VERSION 5.7 ;
  NOWIREEXTENSIONATPIN ON ;
  DIVIDERCHAR "/" ;
  BUSBITCHARS "[]" ;
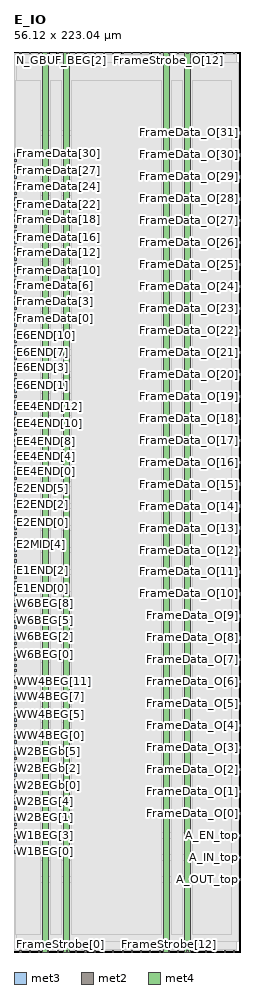
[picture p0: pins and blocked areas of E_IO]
MACRO E_IO
  CLASS BLOCK ;
  FOREIGN E_IO ;
  ORIGIN 0.000 0.000 ;
  SIZE 56.120 BY 223.040 ;
  PIN A_EN_top
    DIRECTION OUTPUT ;
    USE SIGNAL ;
    ANTENNADIFFAREA 0.702900 ;
    PORT
      LAYER met3 ;
        RECT 55.520 28.600 56.120 29.200 ;
    END
  END A_EN_top
  PIN A_IN_top
    DIRECTION OUTPUT ;
    USE SIGNAL ;
    ANTENNADIFFAREA 0.702900 ;
    PORT
      LAYER met3 ;
        RECT 55.520 23.160 56.120 23.760 ;
    END
  END A_IN_top
  PIN A_OUT_top
    DIRECTION INPUT ;
    USE SIGNAL ;
    ANTENNAGATEAREA 0.252000 ;
    PORT
      LAYER met3 ;
        RECT 55.520 17.720 56.120 18.320 ;
    END
  END A_OUT_top
  PIN E1END[0]
    DIRECTION INPUT ;
    USE SIGNAL ;
    ANTENNAGATEAREA 0.878700 ;
    ANTENNADIFFAREA 0.434700 ;
    PORT
      LAYER met3 ;
        RECT 0.000 89.800 0.600 90.400 ;
    END
  END E1END[0]
  PIN E1END[1]
    DIRECTION INPUT ;
    USE SIGNAL ;
    ANTENNAGATEAREA 0.444000 ;
    PORT
      LAYER met3 ;
        RECT 0.000 91.160 0.600 91.760 ;
    END
  END E1END[1]
  PIN E1END[2]
    DIRECTION INPUT ;
    USE SIGNAL ;
    ANTENNAGATEAREA 0.444000 ;
    PORT
      LAYER met3 ;
        RECT 0.000 92.520 0.600 93.120 ;
    END
  END E1END[2]
  PIN E1END[3]
    DIRECTION INPUT ;
    USE SIGNAL ;
    ANTENNAGATEAREA 0.444000 ;
    PORT
      LAYER met3 ;
        RECT 0.000 93.880 0.600 94.480 ;
    END
  END E1END[3]
  PIN E2END[0]
    DIRECTION INPUT ;
    USE SIGNAL ;
    ANTENNAGATEAREA 0.603000 ;
    PORT
      LAYER met3 ;
        RECT 0.000 106.120 0.600 106.720 ;
    END
  END E2END[0]
  PIN E2END[1]
    DIRECTION INPUT ;
    USE SIGNAL ;
    ANTENNAGATEAREA 0.972000 ;
    PORT
      LAYER met3 ;
        RECT 0.000 107.480 0.600 108.080 ;
    END
  END E2END[1]
  PIN E2END[2]
    DIRECTION INPUT ;
    USE SIGNAL ;
    ANTENNAGATEAREA 0.603000 ;
    PORT
      LAYER met3 ;
        RECT 0.000 108.840 0.600 109.440 ;
    END
  END E2END[2]
  PIN E2END[3]
    DIRECTION INPUT ;
    USE SIGNAL ;
    ANTENNAGATEAREA 0.972000 ;
    PORT
      LAYER met3 ;
        RECT 0.000 110.200 0.600 110.800 ;
    END
  END E2END[3]
  PIN E2END[4]
    DIRECTION INPUT ;
    USE SIGNAL ;
    ANTENNAGATEAREA 0.603000 ;
    PORT
      LAYER met3 ;
        RECT 0.000 111.560 0.600 112.160 ;
    END
  END E2END[4]
  PIN E2END[5]
    DIRECTION INPUT ;
    USE SIGNAL ;
    ANTENNAGATEAREA 0.477000 ;
    PORT
      LAYER met3 ;
        RECT 0.000 112.920 0.600 113.520 ;
    END
  END E2END[5]
  PIN E2END[6]
    DIRECTION INPUT ;
    USE SIGNAL ;
    ANTENNAGATEAREA 0.477000 ;
    PORT
      LAYER met3 ;
        RECT 0.000 114.280 0.600 114.880 ;
    END
  END E2END[6]
  PIN E2END[7]
    DIRECTION INPUT ;
    USE SIGNAL ;
    ANTENNAGATEAREA 0.477000 ;
    PORT
      LAYER met3 ;
        RECT 0.000 115.640 0.600 116.240 ;
    END
  END E2END[7]
  PIN E2MID[0]
    DIRECTION INPUT ;
    USE SIGNAL ;
    ANTENNAGATEAREA 0.636000 ;
    PORT
      LAYER met3 ;
        RECT 0.000 95.240 0.600 95.840 ;
    END
  END E2MID[0]
  PIN E2MID[1]
    DIRECTION INPUT ;
    USE SIGNAL ;
    ANTENNAGATEAREA 0.636000 ;
    PORT
      LAYER met3 ;
        RECT 0.000 96.600 0.600 97.200 ;
    END
  END E2MID[1]
  PIN E2MID[2]
    DIRECTION INPUT ;
    USE SIGNAL ;
    ANTENNAGATEAREA 0.636000 ;
    PORT
      LAYER met3 ;
        RECT 0.000 97.960 0.600 98.560 ;
    END
  END E2MID[2]
  PIN E2MID[3]
    DIRECTION INPUT ;
    USE SIGNAL ;
    ANTENNAGATEAREA 0.636000 ;
    PORT
      LAYER met3 ;
        RECT 0.000 99.320 0.600 99.920 ;
    END
  END E2MID[3]
  PIN E2MID[4]
    DIRECTION INPUT ;
    USE SIGNAL ;
    ANTENNAGATEAREA 0.636000 ;
    PORT
      LAYER met3 ;
        RECT 0.000 100.680 0.600 101.280 ;
    END
  END E2MID[4]
  PIN E2MID[5]
    DIRECTION INPUT ;
    USE SIGNAL ;
    ANTENNAGATEAREA 0.636000 ;
    PORT
      LAYER met3 ;
        RECT 0.000 102.040 0.600 102.640 ;
    END
  END E2MID[5]
  PIN E2MID[6]
    DIRECTION INPUT ;
    USE SIGNAL ;
    ANTENNAGATEAREA 0.636000 ;
    PORT
      LAYER met3 ;
        RECT 0.000 103.400 0.600 104.000 ;
    END
  END E2MID[6]
  PIN E2MID[7]
    DIRECTION INPUT ;
    USE SIGNAL ;
    ANTENNAGATEAREA 0.762000 ;
    PORT
      LAYER met3 ;
        RECT 0.000 104.760 0.600 105.360 ;
    END
  END E2MID[7]
  PIN E6END[0]
    DIRECTION INPUT ;
    USE SIGNAL ;
    ANTENNAGATEAREA 0.795000 ;
    PORT
      LAYER met3 ;
        RECT 0.000 138.760 0.600 139.360 ;
    END
  END E6END[0]
  PIN E6END[10]
    DIRECTION INPUT ;
    USE SIGNAL ;
    ANTENNAGATEAREA 0.636000 ;
    PORT
      LAYER met3 ;
        RECT 0.000 152.360 0.600 152.960 ;
    END
  END E6END[10]
  PIN E6END[11]
    DIRECTION INPUT ;
    USE SIGNAL ;
    ANTENNAGATEAREA 0.477000 ;
    PORT
      LAYER met3 ;
        RECT 0.000 153.720 0.600 154.320 ;
    END
  END E6END[11]
  PIN E6END[1]
    DIRECTION INPUT ;
    USE SIGNAL ;
    ANTENNAGATEAREA 0.954000 ;
    PORT
      LAYER met3 ;
        RECT 0.000 140.120 0.600 140.720 ;
    END
  END E6END[1]
  PIN E6END[2]
    DIRECTION INPUT ;
    USE SIGNAL ;
    ANTENNAGATEAREA 0.795000 ;
    PORT
      LAYER met3 ;
        RECT 0.000 141.480 0.600 142.080 ;
    END
  END E6END[2]
  PIN E6END[3]
    DIRECTION INPUT ;
    USE SIGNAL ;
    ANTENNAGATEAREA 0.954000 ;
    PORT
      LAYER met3 ;
        RECT 0.000 142.840 0.600 143.440 ;
    END
  END E6END[3]
  PIN E6END[4]
    DIRECTION INPUT ;
    USE SIGNAL ;
    ANTENNAGATEAREA 0.954000 ;
    PORT
      LAYER met3 ;
        RECT 0.000 144.200 0.600 144.800 ;
    END
  END E6END[4]
  PIN E6END[5]
    DIRECTION INPUT ;
    USE SIGNAL ;
    ANTENNAGATEAREA 0.954000 ;
    PORT
      LAYER met3 ;
        RECT 0.000 145.560 0.600 146.160 ;
    END
  END E6END[5]
  PIN E6END[6]
    DIRECTION INPUT ;
    USE SIGNAL ;
    ANTENNAGATEAREA 0.954000 ;
    PORT
      LAYER met3 ;
        RECT 0.000 146.920 0.600 147.520 ;
    END
  END E6END[6]
  PIN E6END[7]
    DIRECTION INPUT ;
    USE SIGNAL ;
    ANTENNAGATEAREA 0.954000 ;
    PORT
      LAYER met3 ;
        RECT 0.000 148.280 0.600 148.880 ;
    END
  END E6END[7]
  PIN E6END[8]
    DIRECTION INPUT ;
    USE SIGNAL ;
    ANTENNAGATEAREA 0.636000 ;
    PORT
      LAYER met3 ;
        RECT 0.000 149.640 0.600 150.240 ;
    END
  END E6END[8]
  PIN E6END[9]
    DIRECTION INPUT ;
    USE SIGNAL ;
    ANTENNAGATEAREA 0.477000 ;
    PORT
      LAYER met3 ;
        RECT 0.000 151.000 0.600 151.600 ;
    END
  END E6END[9]
  PIN EE4END[0]
    DIRECTION INPUT ;
    USE SIGNAL ;
    ANTENNAGATEAREA 0.477000 ;
    PORT
      LAYER met3 ;
        RECT 0.000 117.000 0.600 117.600 ;
    END
  END EE4END[0]
  PIN EE4END[10]
    DIRECTION INPUT ;
    USE SIGNAL ;
    ANTENNAGATEAREA 0.477000 ;
    PORT
      LAYER met3 ;
        RECT 0.000 130.600 0.600 131.200 ;
    END
  END EE4END[10]
  PIN EE4END[11]
    DIRECTION INPUT ;
    USE SIGNAL ;
    ANTENNAGATEAREA 0.477000 ;
    PORT
      LAYER met3 ;
        RECT 0.000 131.960 0.600 132.560 ;
    END
  END EE4END[11]
  PIN EE4END[12]
    DIRECTION INPUT ;
    USE SIGNAL ;
    ANTENNAGATEAREA 0.477000 ;
    PORT
      LAYER met3 ;
        RECT 0.000 133.320 0.600 133.920 ;
    END
  END EE4END[12]
  PIN EE4END[13]
    DIRECTION INPUT ;
    USE SIGNAL ;
    ANTENNAGATEAREA 0.477000 ;
    PORT
      LAYER met3 ;
        RECT 0.000 134.680 0.600 135.280 ;
    END
  END EE4END[13]
  PIN EE4END[14]
    DIRECTION INPUT ;
    USE SIGNAL ;
    ANTENNAGATEAREA 0.911700 ;
    ANTENNADIFFAREA 0.434700 ;
    PORT
      LAYER met3 ;
        RECT 0.000 136.040 0.600 136.640 ;
    END
  END EE4END[14]
  PIN EE4END[15]
    DIRECTION INPUT ;
    USE SIGNAL ;
    ANTENNAGATEAREA 0.477000 ;
    PORT
      LAYER met3 ;
        RECT 0.000 137.400 0.600 138.000 ;
    END
  END EE4END[15]
  PIN EE4END[1]
    DIRECTION INPUT ;
    USE SIGNAL ;
    ANTENNAGATEAREA 0.477000 ;
    PORT
      LAYER met3 ;
        RECT 0.000 118.360 0.600 118.960 ;
    END
  END EE4END[1]
  PIN EE4END[2]
    DIRECTION INPUT ;
    USE SIGNAL ;
    ANTENNAGATEAREA 0.477000 ;
    PORT
      LAYER met3 ;
        RECT 0.000 119.720 0.600 120.320 ;
    END
  END EE4END[2]
  PIN EE4END[3]
    DIRECTION INPUT ;
    USE SIGNAL ;
    ANTENNAGATEAREA 0.477000 ;
    PORT
      LAYER met3 ;
        RECT 0.000 121.080 0.600 121.680 ;
    END
  END EE4END[3]
  PIN EE4END[4]
    DIRECTION INPUT ;
    USE SIGNAL ;
    ANTENNAGATEAREA 0.477000 ;
    PORT
      LAYER met3 ;
        RECT 0.000 122.440 0.600 123.040 ;
    END
  END EE4END[4]
  PIN EE4END[5]
    DIRECTION INPUT ;
    USE SIGNAL ;
    ANTENNAGATEAREA 0.477000 ;
    PORT
      LAYER met3 ;
        RECT 0.000 123.800 0.600 124.400 ;
    END
  END EE4END[5]
  PIN EE4END[6]
    DIRECTION INPUT ;
    USE SIGNAL ;
    ANTENNAGATEAREA 0.477000 ;
    PORT
      LAYER met3 ;
        RECT 0.000 125.160 0.600 125.760 ;
    END
  END EE4END[6]
  PIN EE4END[7]
    DIRECTION INPUT ;
    USE SIGNAL ;
    ANTENNAGATEAREA 0.477000 ;
    PORT
      LAYER met3 ;
        RECT 0.000 126.520 0.600 127.120 ;
    END
  END EE4END[7]
  PIN EE4END[8]
    DIRECTION INPUT ;
    USE SIGNAL ;
    ANTENNAGATEAREA 0.477000 ;
    PORT
      LAYER met3 ;
        RECT 0.000 127.880 0.600 128.480 ;
    END
  END EE4END[8]
  PIN EE4END[9]
    DIRECTION INPUT ;
    USE SIGNAL ;
    ANTENNAGATEAREA 0.477000 ;
    PORT
      LAYER met3 ;
        RECT 0.000 129.240 0.600 129.840 ;
    END
  END EE4END[9]
  PIN FrameData[0]
    DIRECTION INPUT ;
    USE SIGNAL ;
    ANTENNAGATEAREA 1.070700 ;
    ANTENNADIFFAREA 0.434700 ;
    PORT
      LAYER met3 ;
        RECT 0.000 155.080 0.600 155.680 ;
    END
  END FrameData[0]
  PIN FrameData[10]
    DIRECTION INPUT ;
    USE SIGNAL ;
    ANTENNAGATEAREA 0.795000 ;
    PORT
      LAYER met3 ;
        RECT 0.000 168.680 0.600 169.280 ;
    END
  END FrameData[10]
  PIN FrameData[11]
    DIRECTION INPUT ;
    USE SIGNAL ;
    ANTENNAGATEAREA 1.229700 ;
    ANTENNADIFFAREA 0.434700 ;
    PORT
      LAYER met3 ;
        RECT 0.000 170.040 0.600 170.640 ;
    END
  END FrameData[11]
  PIN FrameData[12]
    DIRECTION INPUT ;
    USE SIGNAL ;
    ANTENNAGATEAREA 1.229700 ;
    ANTENNADIFFAREA 0.434700 ;
    PORT
      LAYER met3 ;
        RECT 0.000 171.400 0.600 172.000 ;
    END
  END FrameData[12]
  PIN FrameData[13]
    DIRECTION INPUT ;
    USE SIGNAL ;
    ANTENNAGATEAREA 0.795000 ;
    PORT
      LAYER met3 ;
        RECT 0.000 172.760 0.600 173.360 ;
    END
  END FrameData[13]
  PIN FrameData[14]
    DIRECTION INPUT ;
    USE SIGNAL ;
    ANTENNAGATEAREA 0.795000 ;
    PORT
      LAYER met3 ;
        RECT 0.000 174.120 0.600 174.720 ;
    END
  END FrameData[14]
  PIN FrameData[15]
    DIRECTION INPUT ;
    USE SIGNAL ;
    ANTENNAGATEAREA 0.795000 ;
    PORT
      LAYER met3 ;
        RECT 0.000 175.480 0.600 176.080 ;
    END
  END FrameData[15]
  PIN FrameData[16]
    DIRECTION INPUT ;
    USE SIGNAL ;
    ANTENNAGATEAREA 0.795000 ;
    PORT
      LAYER met3 ;
        RECT 0.000 176.840 0.600 177.440 ;
    END
  END FrameData[16]
  PIN FrameData[17]
    DIRECTION INPUT ;
    USE SIGNAL ;
    ANTENNAGATEAREA 0.795000 ;
    PORT
      LAYER met3 ;
        RECT 0.000 178.200 0.600 178.800 ;
    END
  END FrameData[17]
  PIN FrameData[18]
    DIRECTION INPUT ;
    USE SIGNAL ;
    ANTENNAGATEAREA 0.795000 ;
    PORT
      LAYER met3 ;
        RECT 0.000 179.560 0.600 180.160 ;
    END
  END FrameData[18]
  PIN FrameData[19]
    DIRECTION INPUT ;
    USE SIGNAL ;
    ANTENNAGATEAREA 0.795000 ;
    PORT
      LAYER met3 ;
        RECT 0.000 180.920 0.600 181.520 ;
    END
  END FrameData[19]
  PIN FrameData[1]
    DIRECTION INPUT ;
    USE SIGNAL ;
    ANTENNAGATEAREA 0.636000 ;
    PORT
      LAYER met3 ;
        RECT 0.000 156.440 0.600 157.040 ;
    END
  END FrameData[1]
  PIN FrameData[20]
    DIRECTION INPUT ;
    USE SIGNAL ;
    ANTENNAGATEAREA 1.229700 ;
    ANTENNADIFFAREA 0.434700 ;
    PORT
      LAYER met3 ;
        RECT 0.000 182.280 0.600 182.880 ;
    END
  END FrameData[20]
  PIN FrameData[21]
    DIRECTION INPUT ;
    USE SIGNAL ;
    ANTENNAGATEAREA 0.795000 ;
    PORT
      LAYER met3 ;
        RECT 0.000 183.640 0.600 184.240 ;
    END
  END FrameData[21]
  PIN FrameData[22]
    DIRECTION INPUT ;
    USE SIGNAL ;
    ANTENNAGATEAREA 0.795000 ;
    PORT
      LAYER met3 ;
        RECT 0.000 185.000 0.600 185.600 ;
    END
  END FrameData[22]
  PIN FrameData[23]
    DIRECTION INPUT ;
    USE SIGNAL ;
    ANTENNAGATEAREA 0.795000 ;
    PORT
      LAYER met3 ;
        RECT 0.000 186.360 0.600 186.960 ;
    END
  END FrameData[23]
  PIN FrameData[24]
    DIRECTION INPUT ;
    USE SIGNAL ;
    ANTENNAGATEAREA 0.795000 ;
    PORT
      LAYER met3 ;
        RECT 0.000 187.720 0.600 188.320 ;
    END
  END FrameData[24]
  PIN FrameData[25]
    DIRECTION INPUT ;
    USE SIGNAL ;
    ANTENNAGATEAREA 0.795000 ;
    PORT
      LAYER met3 ;
        RECT 0.000 189.080 0.600 189.680 ;
    END
  END FrameData[25]
  PIN FrameData[26]
    DIRECTION INPUT ;
    USE SIGNAL ;
    ANTENNAGATEAREA 0.795000 ;
    PORT
      LAYER met3 ;
        RECT 0.000 190.440 0.600 191.040 ;
    END
  END FrameData[26]
  PIN FrameData[27]
    DIRECTION INPUT ;
    USE SIGNAL ;
    ANTENNAGATEAREA 0.795000 ;
    PORT
      LAYER met3 ;
        RECT 0.000 191.800 0.600 192.400 ;
    END
  END FrameData[27]
  PIN FrameData[28]
    DIRECTION INPUT ;
    USE SIGNAL ;
    ANTENNAGATEAREA 0.795000 ;
    PORT
      LAYER met3 ;
        RECT 0.000 193.160 0.600 193.760 ;
    END
  END FrameData[28]
  PIN FrameData[29]
    DIRECTION INPUT ;
    USE SIGNAL ;
    ANTENNAGATEAREA 0.795000 ;
    PORT
      LAYER met3 ;
        RECT 0.000 194.520 0.600 195.120 ;
    END
  END FrameData[29]
  PIN FrameData[2]
    DIRECTION INPUT ;
    USE SIGNAL ;
    ANTENNAGATEAREA 0.636000 ;
    PORT
      LAYER met3 ;
        RECT 0.000 157.800 0.600 158.400 ;
    END
  END FrameData[2]
  PIN FrameData[30]
    DIRECTION INPUT ;
    USE SIGNAL ;
    ANTENNAGATEAREA 1.229700 ;
    ANTENNADIFFAREA 0.434700 ;
    PORT
      LAYER met3 ;
        RECT 0.000 195.880 0.600 196.480 ;
    END
  END FrameData[30]
  PIN FrameData[31]
    DIRECTION INPUT ;
    USE SIGNAL ;
    ANTENNAGATEAREA 0.795000 ;
    PORT
      LAYER met3 ;
        RECT 0.000 197.240 0.600 197.840 ;
    END
  END FrameData[31]
  PIN FrameData[3]
    DIRECTION INPUT ;
    USE SIGNAL ;
    ANTENNAGATEAREA 0.636000 ;
    PORT
      LAYER met3 ;
        RECT 0.000 159.160 0.600 159.760 ;
    END
  END FrameData[3]
  PIN FrameData[4]
    DIRECTION INPUT ;
    USE SIGNAL ;
    ANTENNAGATEAREA 0.636000 ;
    PORT
      LAYER met3 ;
        RECT 0.000 160.520 0.600 161.120 ;
    END
  END FrameData[4]
  PIN FrameData[5]
    DIRECTION INPUT ;
    USE SIGNAL ;
    ANTENNAGATEAREA 0.636000 ;
    PORT
      LAYER met3 ;
        RECT 0.000 161.880 0.600 162.480 ;
    END
  END FrameData[5]
  PIN FrameData[6]
    DIRECTION INPUT ;
    USE SIGNAL ;
    ANTENNAGATEAREA 0.636000 ;
    PORT
      LAYER met3 ;
        RECT 0.000 163.240 0.600 163.840 ;
    END
  END FrameData[6]
  PIN FrameData[7]
    DIRECTION INPUT ;
    USE SIGNAL ;
    ANTENNAGATEAREA 0.636000 ;
    PORT
      LAYER met3 ;
        RECT 0.000 164.600 0.600 165.200 ;
    END
  END FrameData[7]
  PIN FrameData[8]
    DIRECTION INPUT ;
    USE SIGNAL ;
    ANTENNAGATEAREA 0.795000 ;
    PORT
      LAYER met3 ;
        RECT 0.000 165.960 0.600 166.560 ;
    END
  END FrameData[8]
  PIN FrameData[9]
    DIRECTION INPUT ;
    USE SIGNAL ;
    ANTENNAGATEAREA 0.795000 ;
    PORT
      LAYER met3 ;
        RECT 0.000 167.320 0.600 167.920 ;
    END
  END FrameData[9]
  PIN FrameData_O[0]
    DIRECTION OUTPUT ;
    USE SIGNAL ;
    ANTENNADIFFAREA 0.702900 ;
    PORT
      LAYER met3 ;
        RECT 55.520 34.040 56.120 34.640 ;
    END
  END FrameData_O[0]
  PIN FrameData_O[10]
    DIRECTION OUTPUT ;
    USE SIGNAL ;
    ANTENNADIFFAREA 0.702900 ;
    PORT
      LAYER met3 ;
        RECT 55.520 88.440 56.120 89.040 ;
    END
  END FrameData_O[10]
  PIN FrameData_O[11]
    DIRECTION OUTPUT ;
    USE SIGNAL ;
    ANTENNADIFFAREA 0.702900 ;
    PORT
      LAYER met3 ;
        RECT 55.520 93.880 56.120 94.480 ;
    END
  END FrameData_O[11]
  PIN FrameData_O[12]
    DIRECTION OUTPUT ;
    USE SIGNAL ;
    ANTENNADIFFAREA 0.702900 ;
    PORT
      LAYER met3 ;
        RECT 55.520 99.320 56.120 99.920 ;
    END
  END FrameData_O[12]
  PIN FrameData_O[13]
    DIRECTION OUTPUT ;
    USE SIGNAL ;
    ANTENNADIFFAREA 0.702900 ;
    PORT
      LAYER met3 ;
        RECT 55.520 104.760 56.120 105.360 ;
    END
  END FrameData_O[13]
  PIN FrameData_O[14]
    DIRECTION OUTPUT ;
    USE SIGNAL ;
    ANTENNADIFFAREA 0.702900 ;
    PORT
      LAYER met3 ;
        RECT 55.520 110.200 56.120 110.800 ;
    END
  END FrameData_O[14]
  PIN FrameData_O[15]
    DIRECTION OUTPUT ;
    USE SIGNAL ;
    ANTENNADIFFAREA 0.702900 ;
    PORT
      LAYER met3 ;
        RECT 55.520 115.640 56.120 116.240 ;
    END
  END FrameData_O[15]
  PIN FrameData_O[16]
    DIRECTION OUTPUT ;
    USE SIGNAL ;
    ANTENNADIFFAREA 0.702900 ;
    PORT
      LAYER met3 ;
        RECT 55.520 121.080 56.120 121.680 ;
    END
  END FrameData_O[16]
  PIN FrameData_O[17]
    DIRECTION OUTPUT ;
    USE SIGNAL ;
    ANTENNADIFFAREA 0.702900 ;
    PORT
      LAYER met3 ;
        RECT 55.520 126.520 56.120 127.120 ;
    END
  END FrameData_O[17]
  PIN FrameData_O[18]
    DIRECTION OUTPUT ;
    USE SIGNAL ;
    ANTENNADIFFAREA 0.702900 ;
    PORT
      LAYER met3 ;
        RECT 55.520 131.960 56.120 132.560 ;
    END
  END FrameData_O[18]
  PIN FrameData_O[19]
    DIRECTION OUTPUT ;
    USE SIGNAL ;
    ANTENNADIFFAREA 0.702900 ;
    PORT
      LAYER met3 ;
        RECT 55.520 137.400 56.120 138.000 ;
    END
  END FrameData_O[19]
  PIN FrameData_O[1]
    DIRECTION OUTPUT ;
    USE SIGNAL ;
    ANTENNADIFFAREA 0.702900 ;
    PORT
      LAYER met3 ;
        RECT 55.520 39.480 56.120 40.080 ;
    END
  END FrameData_O[1]
  PIN FrameData_O[20]
    DIRECTION OUTPUT ;
    USE SIGNAL ;
    ANTENNADIFFAREA 0.702900 ;
    PORT
      LAYER met3 ;
        RECT 55.520 142.840 56.120 143.440 ;
    END
  END FrameData_O[20]
  PIN FrameData_O[21]
    DIRECTION OUTPUT ;
    USE SIGNAL ;
    ANTENNADIFFAREA 0.702900 ;
    PORT
      LAYER met3 ;
        RECT 55.520 148.280 56.120 148.880 ;
    END
  END FrameData_O[21]
  PIN FrameData_O[22]
    DIRECTION OUTPUT ;
    USE SIGNAL ;
    ANTENNADIFFAREA 0.702900 ;
    PORT
      LAYER met3 ;
        RECT 55.520 153.720 56.120 154.320 ;
    END
  END FrameData_O[22]
  PIN FrameData_O[23]
    DIRECTION OUTPUT ;
    USE SIGNAL ;
    ANTENNADIFFAREA 0.702900 ;
    PORT
      LAYER met3 ;
        RECT 55.520 159.160 56.120 159.760 ;
    END
  END FrameData_O[23]
  PIN FrameData_O[24]
    DIRECTION OUTPUT ;
    USE SIGNAL ;
    ANTENNADIFFAREA 0.702900 ;
    PORT
      LAYER met3 ;
        RECT 55.520 164.600 56.120 165.200 ;
    END
  END FrameData_O[24]
  PIN FrameData_O[25]
    DIRECTION OUTPUT ;
    USE SIGNAL ;
    ANTENNADIFFAREA 0.702900 ;
    PORT
      LAYER met3 ;
        RECT 55.520 170.040 56.120 170.640 ;
    END
  END FrameData_O[25]
  PIN FrameData_O[26]
    DIRECTION OUTPUT ;
    USE SIGNAL ;
    ANTENNADIFFAREA 0.702900 ;
    PORT
      LAYER met3 ;
        RECT 55.520 175.480 56.120 176.080 ;
    END
  END FrameData_O[26]
  PIN FrameData_O[27]
    DIRECTION OUTPUT ;
    USE SIGNAL ;
    ANTENNADIFFAREA 0.702900 ;
    PORT
      LAYER met3 ;
        RECT 55.520 180.920 56.120 181.520 ;
    END
  END FrameData_O[27]
  PIN FrameData_O[28]
    DIRECTION OUTPUT ;
    USE SIGNAL ;
    ANTENNADIFFAREA 0.702900 ;
    PORT
      LAYER met3 ;
        RECT 55.520 186.360 56.120 186.960 ;
    END
  END FrameData_O[28]
  PIN FrameData_O[29]
    DIRECTION OUTPUT ;
    USE SIGNAL ;
    ANTENNADIFFAREA 0.702900 ;
    PORT
      LAYER met3 ;
        RECT 55.520 191.800 56.120 192.400 ;
    END
  END FrameData_O[29]
  PIN FrameData_O[2]
    DIRECTION OUTPUT ;
    USE SIGNAL ;
    ANTENNADIFFAREA 0.702900 ;
    PORT
      LAYER met3 ;
        RECT 55.520 44.920 56.120 45.520 ;
    END
  END FrameData_O[2]
  PIN FrameData_O[30]
    DIRECTION OUTPUT ;
    USE SIGNAL ;
    ANTENNADIFFAREA 0.702900 ;
    PORT
      LAYER met3 ;
        RECT 55.520 197.240 56.120 197.840 ;
    END
  END FrameData_O[30]
  PIN FrameData_O[31]
    DIRECTION OUTPUT ;
    USE SIGNAL ;
    ANTENNADIFFAREA 0.702900 ;
    PORT
      LAYER met3 ;
        RECT 55.520 202.680 56.120 203.280 ;
    END
  END FrameData_O[31]
  PIN FrameData_O[3]
    DIRECTION OUTPUT ;
    USE SIGNAL ;
    ANTENNADIFFAREA 0.702900 ;
    PORT
      LAYER met3 ;
        RECT 55.520 50.360 56.120 50.960 ;
    END
  END FrameData_O[3]
  PIN FrameData_O[4]
    DIRECTION OUTPUT ;
    USE SIGNAL ;
    ANTENNADIFFAREA 0.702900 ;
    PORT
      LAYER met3 ;
        RECT 55.520 55.800 56.120 56.400 ;
    END
  END FrameData_O[4]
  PIN FrameData_O[5]
    DIRECTION OUTPUT ;
    USE SIGNAL ;
    ANTENNADIFFAREA 0.702900 ;
    PORT
      LAYER met3 ;
        RECT 55.520 61.240 56.120 61.840 ;
    END
  END FrameData_O[5]
  PIN FrameData_O[6]
    DIRECTION OUTPUT ;
    USE SIGNAL ;
    ANTENNADIFFAREA 0.702900 ;
    PORT
      LAYER met3 ;
        RECT 55.520 66.680 56.120 67.280 ;
    END
  END FrameData_O[6]
  PIN FrameData_O[7]
    DIRECTION OUTPUT ;
    USE SIGNAL ;
    ANTENNADIFFAREA 0.702900 ;
    PORT
      LAYER met3 ;
        RECT 55.520 72.120 56.120 72.720 ;
    END
  END FrameData_O[7]
  PIN FrameData_O[8]
    DIRECTION OUTPUT ;
    USE SIGNAL ;
    ANTENNADIFFAREA 0.702900 ;
    PORT
      LAYER met3 ;
        RECT 55.520 77.560 56.120 78.160 ;
    END
  END FrameData_O[8]
  PIN FrameData_O[9]
    DIRECTION OUTPUT ;
    USE SIGNAL ;
    ANTENNADIFFAREA 0.702900 ;
    PORT
      LAYER met3 ;
        RECT 55.520 83.000 56.120 83.600 ;
    END
  END FrameData_O[9]
  PIN FrameStrobe[0]
    DIRECTION INPUT ;
    USE SIGNAL ;
    ANTENNAGATEAREA 5.247000 ;
    PORT
      LAYER met2 ;
        RECT 10.670 0.000 10.950 0.280 ;
    END
  END FrameStrobe[0]
  PIN FrameStrobe[10]
    DIRECTION INPUT ;
    USE SIGNAL ;
    ANTENNAGATEAREA 0.593700 ;
    ANTENNADIFFAREA 0.434700 ;
    PORT
      LAYER met2 ;
        RECT 33.670 0.000 33.950 0.280 ;
    END
  END FrameStrobe[10]
  PIN FrameStrobe[11]
    DIRECTION INPUT ;
    USE SIGNAL ;
    ANTENNAGATEAREA 0.593700 ;
    ANTENNADIFFAREA 0.434700 ;
    PORT
      LAYER met2 ;
        RECT 35.970 0.000 36.250 0.280 ;
    END
  END FrameStrobe[11]
  PIN FrameStrobe[12]
    DIRECTION INPUT ;
    USE SIGNAL ;
    ANTENNAGATEAREA 0.593700 ;
    ANTENNADIFFAREA 0.434700 ;
    PORT
      LAYER met2 ;
        RECT 38.270 0.000 38.550 0.280 ;
    END
  END FrameStrobe[12]
  PIN FrameStrobe[13]
    DIRECTION INPUT ;
    USE SIGNAL ;
    ANTENNAGATEAREA 0.593700 ;
    ANTENNADIFFAREA 0.434700 ;
    PORT
      LAYER met2 ;
        RECT 40.570 0.000 40.850 0.280 ;
    END
  END FrameStrobe[13]
  PIN FrameStrobe[14]
    DIRECTION INPUT ;
    USE SIGNAL ;
    ANTENNAGATEAREA 0.159000 ;
    PORT
      LAYER met2 ;
        RECT 42.870 0.000 43.150 0.280 ;
    END
  END FrameStrobe[14]
  PIN FrameStrobe[15]
    DIRECTION INPUT ;
    USE SIGNAL ;
    ANTENNAGATEAREA 0.593700 ;
    ANTENNADIFFAREA 0.434700 ;
    PORT
      LAYER met2 ;
        RECT 45.170 0.000 45.450 0.280 ;
    END
  END FrameStrobe[15]
  PIN FrameStrobe[16]
    DIRECTION INPUT ;
    USE SIGNAL ;
    ANTENNAGATEAREA 0.593700 ;
    ANTENNADIFFAREA 0.434700 ;
    PORT
      LAYER met2 ;
        RECT 47.470 0.000 47.750 0.280 ;
    END
  END FrameStrobe[16]
  PIN FrameStrobe[17]
    DIRECTION INPUT ;
    USE SIGNAL ;
    ANTENNAGATEAREA 0.593700 ;
    ANTENNADIFFAREA 0.434700 ;
    PORT
      LAYER met2 ;
        RECT 49.770 0.000 50.050 0.280 ;
    END
  END FrameStrobe[17]
  PIN FrameStrobe[18]
    DIRECTION INPUT ;
    USE SIGNAL ;
    ANTENNAGATEAREA 0.593700 ;
    ANTENNADIFFAREA 0.434700 ;
    PORT
      LAYER met2 ;
        RECT 52.070 0.000 52.350 0.280 ;
    END
  END FrameStrobe[18]
  PIN FrameStrobe[19]
    DIRECTION INPUT ;
    USE SIGNAL ;
    ANTENNAGATEAREA 0.593700 ;
    ANTENNADIFFAREA 0.434700 ;
    PORT
      LAYER met2 ;
        RECT 54.370 0.000 54.650 0.280 ;
    END
  END FrameStrobe[19]
  PIN FrameStrobe[1]
    DIRECTION INPUT ;
    USE SIGNAL ;
    ANTENNAGATEAREA 5.247000 ;
    PORT
      LAYER met2 ;
        RECT 12.970 0.000 13.250 0.280 ;
    END
  END FrameStrobe[1]
  PIN FrameStrobe[2]
    DIRECTION INPUT ;
    USE SIGNAL ;
    ANTENNAGATEAREA 5.247000 ;
    PORT
      LAYER met2 ;
        RECT 15.270 0.000 15.550 0.280 ;
    END
  END FrameStrobe[2]
  PIN FrameStrobe[3]
    DIRECTION INPUT ;
    USE SIGNAL ;
    ANTENNAGATEAREA 3.975000 ;
    PORT
      LAYER met2 ;
        RECT 17.570 0.000 17.850 0.280 ;
    END
  END FrameStrobe[3]
  PIN FrameStrobe[4]
    DIRECTION INPUT ;
    USE SIGNAL ;
    ANTENNAGATEAREA 0.593700 ;
    ANTENNADIFFAREA 0.434700 ;
    PORT
      LAYER met2 ;
        RECT 19.870 0.000 20.150 0.280 ;
    END
  END FrameStrobe[4]
  PIN FrameStrobe[5]
    DIRECTION INPUT ;
    USE SIGNAL ;
    ANTENNAGATEAREA 0.593700 ;
    ANTENNADIFFAREA 0.434700 ;
    PORT
      LAYER met2 ;
        RECT 22.170 0.000 22.450 0.280 ;
    END
  END FrameStrobe[5]
  PIN FrameStrobe[6]
    DIRECTION INPUT ;
    USE SIGNAL ;
    ANTENNAGATEAREA 0.593700 ;
    ANTENNADIFFAREA 0.434700 ;
    PORT
      LAYER met2 ;
        RECT 24.470 0.000 24.750 0.280 ;
    END
  END FrameStrobe[6]
  PIN FrameStrobe[7]
    DIRECTION INPUT ;
    USE SIGNAL ;
    ANTENNAGATEAREA 0.593700 ;
    ANTENNADIFFAREA 0.434700 ;
    PORT
      LAYER met2 ;
        RECT 26.770 0.000 27.050 0.280 ;
    END
  END FrameStrobe[7]
  PIN FrameStrobe[8]
    DIRECTION INPUT ;
    USE SIGNAL ;
    ANTENNAGATEAREA 0.593700 ;
    ANTENNADIFFAREA 0.434700 ;
    PORT
      LAYER met2 ;
        RECT 29.070 0.000 29.350 0.280 ;
    END
  END FrameStrobe[8]
  PIN FrameStrobe[9]
    DIRECTION INPUT ;
    USE SIGNAL ;
    ANTENNAGATEAREA 0.593700 ;
    ANTENNADIFFAREA 0.434700 ;
    PORT
      LAYER met2 ;
        RECT 31.370 0.000 31.650 0.280 ;
    END
  END FrameStrobe[9]
  PIN FrameStrobe_O[0]
    DIRECTION OUTPUT ;
    USE SIGNAL ;
    ANTENNADIFFAREA 0.702900 ;
    PORT
      LAYER met2 ;
        RECT 10.670 222.760 10.950 223.040 ;
    END
  END FrameStrobe_O[0]
  PIN FrameStrobe_O[10]
    DIRECTION OUTPUT ;
    USE SIGNAL ;
    ANTENNADIFFAREA 0.702900 ;
    PORT
      LAYER met2 ;
        RECT 33.670 222.760 33.950 223.040 ;
    END
  END FrameStrobe_O[10]
  PIN FrameStrobe_O[11]
    DIRECTION OUTPUT ;
    USE SIGNAL ;
    ANTENNADIFFAREA 0.702900 ;
    PORT
      LAYER met2 ;
        RECT 35.970 222.760 36.250 223.040 ;
    END
  END FrameStrobe_O[11]
  PIN FrameStrobe_O[12]
    DIRECTION OUTPUT ;
    USE SIGNAL ;
    ANTENNADIFFAREA 0.702900 ;
    PORT
      LAYER met2 ;
        RECT 38.270 222.760 38.550 223.040 ;
    END
  END FrameStrobe_O[12]
  PIN FrameStrobe_O[13]
    DIRECTION OUTPUT ;
    USE SIGNAL ;
    ANTENNADIFFAREA 0.702900 ;
    PORT
      LAYER met2 ;
        RECT 40.570 222.760 40.850 223.040 ;
    END
  END FrameStrobe_O[13]
  PIN FrameStrobe_O[14]
    DIRECTION OUTPUT ;
    USE SIGNAL ;
    ANTENNADIFFAREA 0.702900 ;
    PORT
      LAYER met2 ;
        RECT 42.870 222.760 43.150 223.040 ;
    END
  END FrameStrobe_O[14]
  PIN FrameStrobe_O[15]
    DIRECTION OUTPUT ;
    USE SIGNAL ;
    ANTENNADIFFAREA 0.702900 ;
    PORT
      LAYER met2 ;
        RECT 45.170 222.760 45.450 223.040 ;
    END
  END FrameStrobe_O[15]
  PIN FrameStrobe_O[16]
    DIRECTION OUTPUT ;
    USE SIGNAL ;
    ANTENNADIFFAREA 0.702900 ;
    PORT
      LAYER met2 ;
        RECT 47.470 222.760 47.750 223.040 ;
    END
  END FrameStrobe_O[16]
  PIN FrameStrobe_O[17]
    DIRECTION OUTPUT ;
    USE SIGNAL ;
    ANTENNADIFFAREA 0.702900 ;
    PORT
      LAYER met2 ;
        RECT 49.770 222.760 50.050 223.040 ;
    END
  END FrameStrobe_O[17]
  PIN FrameStrobe_O[18]
    DIRECTION OUTPUT ;
    USE SIGNAL ;
    ANTENNADIFFAREA 0.702900 ;
    PORT
      LAYER met2 ;
        RECT 52.070 222.760 52.350 223.040 ;
    END
  END FrameStrobe_O[18]
  PIN FrameStrobe_O[19]
    DIRECTION OUTPUT ;
    USE SIGNAL ;
    ANTENNADIFFAREA 0.702900 ;
    PORT
      LAYER met2 ;
        RECT 54.370 222.760 54.650 223.040 ;
    END
  END FrameStrobe_O[19]
  PIN FrameStrobe_O[1]
    DIRECTION OUTPUT ;
    USE SIGNAL ;
    ANTENNADIFFAREA 0.702900 ;
    PORT
      LAYER met2 ;
        RECT 12.970 222.760 13.250 223.040 ;
    END
  END FrameStrobe_O[1]
  PIN FrameStrobe_O[2]
    DIRECTION OUTPUT ;
    USE SIGNAL ;
    ANTENNADIFFAREA 0.702900 ;
    PORT
      LAYER met2 ;
        RECT 15.270 222.760 15.550 223.040 ;
    END
  END FrameStrobe_O[2]
  PIN FrameStrobe_O[3]
    DIRECTION OUTPUT ;
    USE SIGNAL ;
    ANTENNADIFFAREA 0.702900 ;
    PORT
      LAYER met2 ;
        RECT 17.570 222.760 17.850 223.040 ;
    END
  END FrameStrobe_O[3]
  PIN FrameStrobe_O[4]
    DIRECTION OUTPUT ;
    USE SIGNAL ;
    ANTENNADIFFAREA 0.702900 ;
    PORT
      LAYER met2 ;
        RECT 19.870 222.760 20.150 223.040 ;
    END
  END FrameStrobe_O[4]
  PIN FrameStrobe_O[5]
    DIRECTION OUTPUT ;
    USE SIGNAL ;
    ANTENNADIFFAREA 0.702900 ;
    PORT
      LAYER met2 ;
        RECT 22.170 222.760 22.450 223.040 ;
    END
  END FrameStrobe_O[5]
  PIN FrameStrobe_O[6]
    DIRECTION OUTPUT ;
    USE SIGNAL ;
    ANTENNADIFFAREA 0.702900 ;
    PORT
      LAYER met2 ;
        RECT 24.470 222.760 24.750 223.040 ;
    END
  END FrameStrobe_O[6]
  PIN FrameStrobe_O[7]
    DIRECTION OUTPUT ;
    USE SIGNAL ;
    ANTENNADIFFAREA 0.702900 ;
    PORT
      LAYER met2 ;
        RECT 26.770 222.760 27.050 223.040 ;
    END
  END FrameStrobe_O[7]
  PIN FrameStrobe_O[8]
    DIRECTION OUTPUT ;
    USE SIGNAL ;
    ANTENNADIFFAREA 0.702900 ;
    PORT
      LAYER met2 ;
        RECT 29.070 222.760 29.350 223.040 ;
    END
  END FrameStrobe_O[8]
  PIN FrameStrobe_O[9]
    DIRECTION OUTPUT ;
    USE SIGNAL ;
    ANTENNADIFFAREA 0.702900 ;
    PORT
      LAYER met2 ;
        RECT 31.370 222.760 31.650 223.040 ;
    END
  END FrameStrobe_O[9]
  PIN N_GBUF_BEG[0]
    DIRECTION OUTPUT ;
    USE SIGNAL ;
    ANTENNADIFFAREA 0.702900 ;
    PORT
      LAYER met2 ;
        RECT 1.470 222.760 1.750 223.040 ;
    END
  END N_GBUF_BEG[0]
  PIN N_GBUF_BEG[1]
    DIRECTION OUTPUT ;
    USE SIGNAL ;
    ANTENNADIFFAREA 0.702900 ;
    PORT
      LAYER met2 ;
        RECT 3.770 222.760 4.050 223.040 ;
    END
  END N_GBUF_BEG[1]
  PIN N_GBUF_BEG[2]
    DIRECTION OUTPUT ;
    USE SIGNAL ;
    ANTENNADIFFAREA 0.702900 ;
    PORT
      LAYER met2 ;
        RECT 6.070 222.760 6.350 223.040 ;
    END
  END N_GBUF_BEG[2]
  PIN N_GBUF_BEG[3]
    DIRECTION OUTPUT ;
    USE SIGNAL ;
    ANTENNADIFFAREA 0.702900 ;
    PORT
      LAYER met2 ;
        RECT 8.370 222.760 8.650 223.040 ;
    END
  END N_GBUF_BEG[3]
  PIN N_GBUF_END[0]
    DIRECTION INPUT ;
    USE SIGNAL ;
    ANTENNAGATEAREA 0.852000 ;
    PORT
      LAYER met2 ;
        RECT 1.470 0.000 1.750 0.280 ;
    END
  END N_GBUF_END[0]
  PIN N_GBUF_END[1]
    DIRECTION INPUT ;
    USE SIGNAL ;
    ANTENNAGATEAREA 0.752700 ;
    ANTENNADIFFAREA 0.434700 ;
    PORT
      LAYER met2 ;
        RECT 3.770 0.000 4.050 0.280 ;
    END
  END N_GBUF_END[1]
  PIN N_GBUF_END[2]
    DIRECTION INPUT ;
    USE SIGNAL ;
    ANTENNAGATEAREA 0.752700 ;
    ANTENNADIFFAREA 0.434700 ;
    PORT
      LAYER met2 ;
        RECT 6.070 0.000 6.350 0.280 ;
    END
  END N_GBUF_END[2]
  PIN N_GBUF_END[3]
    DIRECTION INPUT ;
    USE SIGNAL ;
    ANTENNAGATEAREA 1.187400 ;
    ANTENNADIFFAREA 0.869400 ;
    PORT
      LAYER met2 ;
        RECT 8.370 0.000 8.650 0.280 ;
    END
  END N_GBUF_END[3]
  PIN VGND
    DIRECTION INOUT ;
    USE GROUND ;
    PORT
      LAYER met4 ;
        RECT 12.260 0.000 13.860 223.040 ;
    END
    PORT
      LAYER met4 ;
        RECT 42.260 0.000 43.860 223.040 ;
    END
  END VGND
  PIN VPWR
    DIRECTION INOUT ;
    USE POWER ;
    PORT
      LAYER met4 ;
        RECT 6.960 0.000 8.560 223.040 ;
    END
    PORT
      LAYER met4 ;
        RECT 36.960 0.000 38.560 223.040 ;
    END
  END VPWR
  PIN W1BEG[0]
    DIRECTION OUTPUT ;
    USE SIGNAL ;
    ANTENNADIFFAREA 0.702900 ;
    PORT
      LAYER met3 ;
        RECT 0.000 24.520 0.600 25.120 ;
    END
  END W1BEG[0]
  PIN W1BEG[1]
    DIRECTION OUTPUT ;
    USE SIGNAL ;
    ANTENNADIFFAREA 0.702900 ;
    PORT
      LAYER met3 ;
        RECT 0.000 25.880 0.600 26.480 ;
    END
  END W1BEG[1]
  PIN W1BEG[2]
    DIRECTION OUTPUT ;
    USE SIGNAL ;
    ANTENNADIFFAREA 0.702900 ;
    PORT
      LAYER met3 ;
        RECT 0.000 27.240 0.600 27.840 ;
    END
  END W1BEG[2]
  PIN W1BEG[3]
    DIRECTION OUTPUT ;
    USE SIGNAL ;
    ANTENNADIFFAREA 0.702900 ;
    PORT
      LAYER met3 ;
        RECT 0.000 28.600 0.600 29.200 ;
    END
  END W1BEG[3]
  PIN W2BEG[0]
    DIRECTION OUTPUT ;
    USE SIGNAL ;
    ANTENNADIFFAREA 0.702900 ;
    PORT
      LAYER met3 ;
        RECT 0.000 29.960 0.600 30.560 ;
    END
  END W2BEG[0]
  PIN W2BEG[1]
    DIRECTION OUTPUT ;
    USE SIGNAL ;
    ANTENNADIFFAREA 0.702900 ;
    PORT
      LAYER met3 ;
        RECT 0.000 31.320 0.600 31.920 ;
    END
  END W2BEG[1]
  PIN W2BEG[2]
    DIRECTION OUTPUT ;
    USE SIGNAL ;
    ANTENNADIFFAREA 0.702900 ;
    PORT
      LAYER met3 ;
        RECT 0.000 32.680 0.600 33.280 ;
    END
  END W2BEG[2]
  PIN W2BEG[3]
    DIRECTION OUTPUT ;
    USE SIGNAL ;
    ANTENNADIFFAREA 0.702900 ;
    PORT
      LAYER met3 ;
        RECT 0.000 34.040 0.600 34.640 ;
    END
  END W2BEG[3]
  PIN W2BEG[4]
    DIRECTION OUTPUT ;
    USE SIGNAL ;
    ANTENNADIFFAREA 0.702900 ;
    PORT
      LAYER met3 ;
        RECT 0.000 35.400 0.600 36.000 ;
    END
  END W2BEG[4]
  PIN W2BEG[5]
    DIRECTION OUTPUT ;
    USE SIGNAL ;
    ANTENNADIFFAREA 0.702900 ;
    PORT
      LAYER met3 ;
        RECT 0.000 36.760 0.600 37.360 ;
    END
  END W2BEG[5]
  PIN W2BEG[6]
    DIRECTION OUTPUT ;
    USE SIGNAL ;
    ANTENNADIFFAREA 0.702900 ;
    PORT
      LAYER met3 ;
        RECT 0.000 38.120 0.600 38.720 ;
    END
  END W2BEG[6]
  PIN W2BEG[7]
    DIRECTION OUTPUT ;
    USE SIGNAL ;
    ANTENNADIFFAREA 0.702900 ;
    PORT
      LAYER met3 ;
        RECT 0.000 39.480 0.600 40.080 ;
    END
  END W2BEG[7]
  PIN W2BEGb[0]
    DIRECTION OUTPUT ;
    USE SIGNAL ;
    ANTENNADIFFAREA 0.702900 ;
    PORT
      LAYER met3 ;
        RECT 0.000 40.840 0.600 41.440 ;
    END
  END W2BEGb[0]
  PIN W2BEGb[1]
    DIRECTION OUTPUT ;
    USE SIGNAL ;
    ANTENNADIFFAREA 0.702900 ;
    PORT
      LAYER met3 ;
        RECT 0.000 42.200 0.600 42.800 ;
    END
  END W2BEGb[1]
  PIN W2BEGb[2]
    DIRECTION OUTPUT ;
    USE SIGNAL ;
    ANTENNADIFFAREA 0.702900 ;
    PORT
      LAYER met3 ;
        RECT 0.000 43.560 0.600 44.160 ;
    END
  END W2BEGb[2]
  PIN W2BEGb[3]
    DIRECTION OUTPUT ;
    USE SIGNAL ;
    ANTENNADIFFAREA 0.702900 ;
    PORT
      LAYER met3 ;
        RECT 0.000 44.920 0.600 45.520 ;
    END
  END W2BEGb[3]
  PIN W2BEGb[4]
    DIRECTION OUTPUT ;
    USE SIGNAL ;
    ANTENNADIFFAREA 0.702900 ;
    PORT
      LAYER met3 ;
        RECT 0.000 46.280 0.600 46.880 ;
    END
  END W2BEGb[4]
  PIN W2BEGb[5]
    DIRECTION OUTPUT ;
    USE SIGNAL ;
    ANTENNADIFFAREA 0.702900 ;
    PORT
      LAYER met3 ;
        RECT 0.000 47.640 0.600 48.240 ;
    END
  END W2BEGb[5]
  PIN W2BEGb[6]
    DIRECTION OUTPUT ;
    USE SIGNAL ;
    ANTENNADIFFAREA 0.702900 ;
    PORT
      LAYER met3 ;
        RECT 0.000 49.000 0.600 49.600 ;
    END
  END W2BEGb[6]
  PIN W2BEGb[7]
    DIRECTION OUTPUT ;
    USE SIGNAL ;
    ANTENNADIFFAREA 0.702900 ;
    PORT
      LAYER met3 ;
        RECT 0.000 50.360 0.600 50.960 ;
    END
  END W2BEGb[7]
  PIN W6BEG[0]
    DIRECTION OUTPUT ;
    USE SIGNAL ;
    ANTENNADIFFAREA 0.702900 ;
    PORT
      LAYER met3 ;
        RECT 0.000 73.480 0.600 74.080 ;
    END
  END W6BEG[0]
  PIN W6BEG[10]
    DIRECTION OUTPUT ;
    USE SIGNAL ;
    ANTENNADIFFAREA 0.702900 ;
    PORT
      LAYER met3 ;
        RECT 0.000 87.080 0.600 87.680 ;
    END
  END W6BEG[10]
  PIN W6BEG[11]
    DIRECTION OUTPUT ;
    USE SIGNAL ;
    ANTENNADIFFAREA 0.702900 ;
    PORT
      LAYER met3 ;
        RECT 0.000 88.440 0.600 89.040 ;
    END
  END W6BEG[11]
  PIN W6BEG[1]
    DIRECTION OUTPUT ;
    USE SIGNAL ;
    ANTENNADIFFAREA 0.702900 ;
    PORT
      LAYER met3 ;
        RECT 0.000 74.840 0.600 75.440 ;
    END
  END W6BEG[1]
  PIN W6BEG[2]
    DIRECTION OUTPUT ;
    USE SIGNAL ;
    ANTENNADIFFAREA 0.702900 ;
    PORT
      LAYER met3 ;
        RECT 0.000 76.200 0.600 76.800 ;
    END
  END W6BEG[2]
  PIN W6BEG[3]
    DIRECTION OUTPUT ;
    USE SIGNAL ;
    ANTENNADIFFAREA 0.702900 ;
    PORT
      LAYER met3 ;
        RECT 0.000 77.560 0.600 78.160 ;
    END
  END W6BEG[3]
  PIN W6BEG[4]
    DIRECTION OUTPUT ;
    USE SIGNAL ;
    ANTENNADIFFAREA 0.702900 ;
    PORT
      LAYER met3 ;
        RECT 0.000 78.920 0.600 79.520 ;
    END
  END W6BEG[4]
  PIN W6BEG[5]
    DIRECTION OUTPUT ;
    USE SIGNAL ;
    ANTENNADIFFAREA 0.702900 ;
    PORT
      LAYER met3 ;
        RECT 0.000 80.280 0.600 80.880 ;
    END
  END W6BEG[5]
  PIN W6BEG[6]
    DIRECTION OUTPUT ;
    USE SIGNAL ;
    ANTENNADIFFAREA 0.702900 ;
    PORT
      LAYER met3 ;
        RECT 0.000 81.640 0.600 82.240 ;
    END
  END W6BEG[6]
  PIN W6BEG[7]
    DIRECTION OUTPUT ;
    USE SIGNAL ;
    ANTENNADIFFAREA 0.702900 ;
    PORT
      LAYER met3 ;
        RECT 0.000 83.000 0.600 83.600 ;
    END
  END W6BEG[7]
  PIN W6BEG[8]
    DIRECTION OUTPUT ;
    USE SIGNAL ;
    ANTENNADIFFAREA 0.702900 ;
    PORT
      LAYER met3 ;
        RECT 0.000 84.360 0.600 84.960 ;
    END
  END W6BEG[8]
  PIN W6BEG[9]
    DIRECTION OUTPUT ;
    USE SIGNAL ;
    ANTENNADIFFAREA 0.702900 ;
    PORT
      LAYER met3 ;
        RECT 0.000 85.720 0.600 86.320 ;
    END
  END W6BEG[9]
  PIN WW4BEG[0]
    DIRECTION OUTPUT ;
    USE SIGNAL ;
    ANTENNADIFFAREA 0.702900 ;
    PORT
      LAYER met3 ;
        RECT 0.000 51.720 0.600 52.320 ;
    END
  END WW4BEG[0]
  PIN WW4BEG[10]
    DIRECTION OUTPUT ;
    USE SIGNAL ;
    ANTENNADIFFAREA 0.702900 ;
    PORT
      LAYER met3 ;
        RECT 0.000 65.320 0.600 65.920 ;
    END
  END WW4BEG[10]
  PIN WW4BEG[11]
    DIRECTION OUTPUT ;
    USE SIGNAL ;
    ANTENNADIFFAREA 0.702900 ;
    PORT
      LAYER met3 ;
        RECT 0.000 66.680 0.600 67.280 ;
    END
  END WW4BEG[11]
  PIN WW4BEG[12]
    DIRECTION OUTPUT ;
    USE SIGNAL ;
    ANTENNADIFFAREA 0.702900 ;
    PORT
      LAYER met3 ;
        RECT 0.000 68.040 0.600 68.640 ;
    END
  END WW4BEG[12]
  PIN WW4BEG[13]
    DIRECTION OUTPUT ;
    USE SIGNAL ;
    ANTENNADIFFAREA 0.702900 ;
    PORT
      LAYER met3 ;
        RECT 0.000 69.400 0.600 70.000 ;
    END
  END WW4BEG[13]
  PIN WW4BEG[14]
    DIRECTION OUTPUT ;
    USE SIGNAL ;
    ANTENNADIFFAREA 0.702900 ;
    PORT
      LAYER met3 ;
        RECT 0.000 70.760 0.600 71.360 ;
    END
  END WW4BEG[14]
  PIN WW4BEG[15]
    DIRECTION OUTPUT ;
    USE SIGNAL ;
    ANTENNADIFFAREA 0.702900 ;
    PORT
      LAYER met3 ;
        RECT 0.000 72.120 0.600 72.720 ;
    END
  END WW4BEG[15]
  PIN WW4BEG[1]
    DIRECTION OUTPUT ;
    USE SIGNAL ;
    ANTENNADIFFAREA 0.702900 ;
    PORT
      LAYER met3 ;
        RECT 0.000 53.080 0.600 53.680 ;
    END
  END WW4BEG[1]
  PIN WW4BEG[2]
    DIRECTION OUTPUT ;
    USE SIGNAL ;
    ANTENNADIFFAREA 0.702900 ;
    PORT
      LAYER met3 ;
        RECT 0.000 54.440 0.600 55.040 ;
    END
  END WW4BEG[2]
  PIN WW4BEG[3]
    DIRECTION OUTPUT ;
    USE SIGNAL ;
    ANTENNADIFFAREA 0.702900 ;
    PORT
      LAYER met3 ;
        RECT 0.000 55.800 0.600 56.400 ;
    END
  END WW4BEG[3]
  PIN WW4BEG[4]
    DIRECTION OUTPUT ;
    USE SIGNAL ;
    ANTENNADIFFAREA 0.702900 ;
    PORT
      LAYER met3 ;
        RECT 0.000 57.160 0.600 57.760 ;
    END
  END WW4BEG[4]
  PIN WW4BEG[5]
    DIRECTION OUTPUT ;
    USE SIGNAL ;
    ANTENNADIFFAREA 0.702900 ;
    PORT
      LAYER met3 ;
        RECT 0.000 58.520 0.600 59.120 ;
    END
  END WW4BEG[5]
  PIN WW4BEG[6]
    DIRECTION OUTPUT ;
    USE SIGNAL ;
    ANTENNADIFFAREA 0.702900 ;
    PORT
      LAYER met3 ;
        RECT 0.000 59.880 0.600 60.480 ;
    END
  END WW4BEG[6]
  PIN WW4BEG[7]
    DIRECTION OUTPUT ;
    USE SIGNAL ;
    ANTENNADIFFAREA 0.702900 ;
    PORT
      LAYER met3 ;
        RECT 0.000 61.240 0.600 61.840 ;
    END
  END WW4BEG[7]
  PIN WW4BEG[8]
    DIRECTION OUTPUT ;
    USE SIGNAL ;
    ANTENNADIFFAREA 0.702900 ;
    PORT
      LAYER met3 ;
        RECT 0.000 62.600 0.600 63.200 ;
    END
  END WW4BEG[8]
  PIN WW4BEG[9]
    DIRECTION OUTPUT ;
    USE SIGNAL ;
    ANTENNADIFFAREA 0.702900 ;
    PORT
      LAYER met3 ;
        RECT 0.000 63.960 0.600 64.560 ;
    END
  END WW4BEG[9]
  OBS
      LAYER nwell ;
        RECT 2.570 2.635 53.550 220.405 ;
      LAYER li1 ;
        RECT 2.760 2.635 53.360 220.405 ;
      LAYER met1 ;
        RECT 0.160 2.080 55.130 220.560 ;
      LAYER met2 ;
        RECT 0.160 222.480 1.190 222.760 ;
        RECT 2.030 222.480 3.490 222.760 ;
        RECT 4.330 222.480 5.790 222.760 ;
        RECT 6.630 222.480 8.090 222.760 ;
        RECT 8.930 222.480 10.390 222.760 ;
        RECT 11.230 222.480 12.690 222.760 ;
        RECT 13.530 222.480 14.990 222.760 ;
        RECT 15.830 222.480 17.290 222.760 ;
        RECT 18.130 222.480 19.590 222.760 ;
        RECT 20.430 222.480 21.890 222.760 ;
        RECT 22.730 222.480 24.190 222.760 ;
        RECT 25.030 222.480 26.490 222.760 ;
        RECT 27.330 222.480 28.790 222.760 ;
        RECT 29.630 222.480 31.090 222.760 ;
        RECT 31.930 222.480 33.390 222.760 ;
        RECT 34.230 222.480 35.690 222.760 ;
        RECT 36.530 222.480 37.990 222.760 ;
        RECT 38.830 222.480 40.290 222.760 ;
        RECT 41.130 222.480 42.590 222.760 ;
        RECT 43.430 222.480 44.890 222.760 ;
        RECT 45.730 222.480 47.190 222.760 ;
        RECT 48.030 222.480 49.490 222.760 ;
        RECT 50.330 222.480 51.790 222.760 ;
        RECT 52.630 222.480 54.090 222.760 ;
        RECT 54.930 222.480 55.110 222.760 ;
        RECT 0.160 0.560 55.110 222.480 ;
        RECT 0.160 0.270 1.190 0.560 ;
        RECT 2.030 0.270 3.490 0.560 ;
        RECT 4.330 0.270 5.790 0.560 ;
        RECT 6.630 0.270 8.090 0.560 ;
        RECT 8.930 0.270 10.390 0.560 ;
        RECT 11.230 0.270 12.690 0.560 ;
        RECT 13.530 0.270 14.990 0.560 ;
        RECT 15.830 0.270 17.290 0.560 ;
        RECT 18.130 0.270 19.590 0.560 ;
        RECT 20.430 0.270 21.890 0.560 ;
        RECT 22.730 0.270 24.190 0.560 ;
        RECT 25.030 0.270 26.490 0.560 ;
        RECT 27.330 0.270 28.790 0.560 ;
        RECT 29.630 0.270 31.090 0.560 ;
        RECT 31.930 0.270 33.390 0.560 ;
        RECT 34.230 0.270 35.690 0.560 ;
        RECT 36.530 0.270 37.990 0.560 ;
        RECT 38.830 0.270 40.290 0.560 ;
        RECT 41.130 0.270 42.590 0.560 ;
        RECT 43.430 0.270 44.890 0.560 ;
        RECT 45.730 0.270 47.190 0.560 ;
        RECT 48.030 0.270 49.490 0.560 ;
        RECT 50.330 0.270 51.790 0.560 ;
        RECT 52.630 0.270 54.090 0.560 ;
        RECT 54.930 0.270 55.110 0.560 ;
      LAYER met3 ;
        RECT 0.600 203.680 55.520 220.485 ;
        RECT 0.600 202.280 55.120 203.680 ;
        RECT 0.600 198.240 55.520 202.280 ;
        RECT 1.000 196.840 55.120 198.240 ;
        RECT 1.000 192.800 55.520 196.840 ;
        RECT 1.000 191.400 55.120 192.800 ;
        RECT 1.000 187.360 55.520 191.400 ;
        RECT 1.000 185.960 55.120 187.360 ;
        RECT 1.000 181.920 55.520 185.960 ;
        RECT 1.000 180.520 55.120 181.920 ;
        RECT 1.000 176.480 55.520 180.520 ;
        RECT 1.000 175.080 55.120 176.480 ;
        RECT 1.000 171.040 55.520 175.080 ;
        RECT 1.000 169.640 55.120 171.040 ;
        RECT 1.000 165.600 55.520 169.640 ;
        RECT 1.000 164.200 55.120 165.600 ;
        RECT 1.000 160.160 55.520 164.200 ;
        RECT 1.000 158.760 55.120 160.160 ;
        RECT 1.000 154.720 55.520 158.760 ;
        RECT 1.000 153.320 55.120 154.720 ;
        RECT 1.000 149.280 55.520 153.320 ;
        RECT 1.000 147.880 55.120 149.280 ;
        RECT 1.000 143.840 55.520 147.880 ;
        RECT 1.000 142.440 55.120 143.840 ;
        RECT 1.000 138.400 55.520 142.440 ;
        RECT 1.000 137.000 55.120 138.400 ;
        RECT 1.000 132.960 55.520 137.000 ;
        RECT 1.000 131.560 55.120 132.960 ;
        RECT 1.000 127.520 55.520 131.560 ;
        RECT 1.000 126.120 55.120 127.520 ;
        RECT 1.000 122.080 55.520 126.120 ;
        RECT 1.000 120.680 55.120 122.080 ;
        RECT 1.000 116.640 55.520 120.680 ;
        RECT 1.000 115.240 55.120 116.640 ;
        RECT 1.000 111.200 55.520 115.240 ;
        RECT 1.000 109.800 55.120 111.200 ;
        RECT 1.000 105.760 55.520 109.800 ;
        RECT 1.000 104.360 55.120 105.760 ;
        RECT 1.000 100.320 55.520 104.360 ;
        RECT 1.000 98.920 55.120 100.320 ;
        RECT 1.000 94.880 55.520 98.920 ;
        RECT 1.000 93.480 55.120 94.880 ;
        RECT 1.000 89.440 55.520 93.480 ;
        RECT 1.000 88.040 55.120 89.440 ;
        RECT 1.000 84.000 55.520 88.040 ;
        RECT 1.000 82.600 55.120 84.000 ;
        RECT 1.000 78.560 55.520 82.600 ;
        RECT 1.000 77.160 55.120 78.560 ;
        RECT 1.000 73.120 55.520 77.160 ;
        RECT 1.000 71.720 55.120 73.120 ;
        RECT 1.000 67.680 55.520 71.720 ;
        RECT 1.000 66.280 55.120 67.680 ;
        RECT 1.000 62.240 55.520 66.280 ;
        RECT 1.000 60.840 55.120 62.240 ;
        RECT 1.000 56.800 55.520 60.840 ;
        RECT 1.000 55.400 55.120 56.800 ;
        RECT 1.000 51.360 55.520 55.400 ;
        RECT 1.000 49.960 55.120 51.360 ;
        RECT 1.000 45.920 55.520 49.960 ;
        RECT 1.000 44.520 55.120 45.920 ;
        RECT 1.000 40.480 55.520 44.520 ;
        RECT 1.000 39.080 55.120 40.480 ;
        RECT 1.000 35.040 55.520 39.080 ;
        RECT 1.000 33.640 55.120 35.040 ;
        RECT 1.000 29.600 55.520 33.640 ;
        RECT 1.000 28.200 55.120 29.600 ;
        RECT 1.000 24.160 55.520 28.200 ;
        RECT 1.000 24.120 55.120 24.160 ;
        RECT 0.600 22.760 55.120 24.120 ;
        RECT 0.600 18.720 55.520 22.760 ;
        RECT 0.600 17.320 55.120 18.720 ;
        RECT 0.600 2.555 55.520 17.320 ;
      LAYER met4 ;
        RECT 0.310 4.255 6.560 216.065 ;
        RECT 8.960 4.255 11.860 216.065 ;
        RECT 14.260 4.255 36.560 216.065 ;
        RECT 38.960 4.255 41.860 216.065 ;
        RECT 44.260 4.255 53.985 216.065 ;
  END
END E_IO
END LIBRARY

